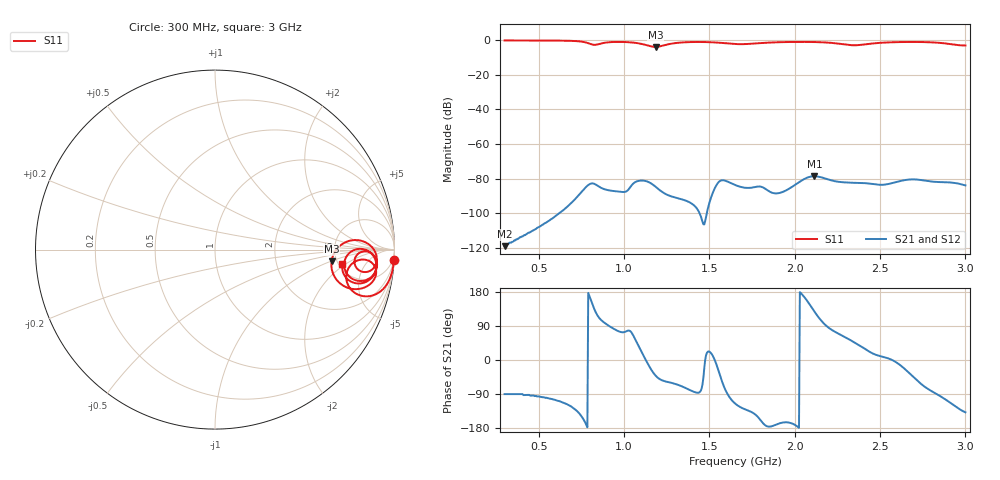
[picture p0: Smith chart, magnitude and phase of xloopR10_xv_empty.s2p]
! xloopR10_xv_empty, gap C 0.80 pF
! simulated by sim/fixtures_fdtd.py (S12 = S21, S22 not computed)
# HZ S RI R 50
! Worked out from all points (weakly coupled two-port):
!   541 points, 300 MHz to 3 GHz, reference 50 ohm
!   highest |S21| = -78.68 dB at 2.115 GHz (marker M1); lowest = -119.2 dB at 300 MHz (marker M2)
!   lowest |S11| = -3.7 dB at 1.185 GHz (marker M3), VSWR 4.76, Z = 226 - j51.2 ohm
!   |S11| at or under -10 dB: nowhere
!   |S22| runs from - to - dB; largest |S21 - S12| = 0
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3e8  0.9972 -0.0595  0 -1.1e-06  0 -1.1e-06  0 0
6.3e8  0.9732 -0.1644  -3.7e-06 -1.01e-05  -3.7e-06 -1.01e-05  0 0
7.5e8  0.8918 -0.2505  -3.44e-05 -2.13e-05  -3.44e-05 -2.13e-05  0 0
8.2e8  0.7314 -0.1622  -5.55e-05 4.54e-05  -5.55e-05 4.54e-05  0 0
8.65e8  0.8129 -0.0559  -1.46e-05 5.19e-05  -1.46e-05 5.19e-05  0 0
9.65e8  0.8974 -0.135  9.9e-06 4.08e-05  9.9e-06 4.08e-05  0 0
1.09e9  0.7867 -0.2205  7.33e-05 4.59e-05  7.33e-05 4.59e-05  0 0
1.185e9  0.6493 -0.0651  4.34e-05 -3.81e-05  4.34e-05 -3.81e-05  0 0
1.2e9  0.6614 -0.024  3.37e-05 -3.71e-05  3.37e-05 -3.71e-05  0 0
1.265e9  0.7833 0.0532  1.65e-05 -2.74e-05  1.65e-05 -2.74e-05  0 0
1.385e9  0.8961 -0.0224  3.8e-06 -2e-05  3.8e-06 -2e-05  0 0
1.545e9  0.8589 -0.1207  6.62e-05 -1.98e-05  6.62e-05 -1.98e-05  0 0
1.65e9  0.783 -0.0931  -2.71e-05 -5.93e-05  -2.71e-05 -5.93e-05  0 0
1.805e9  0.8419 -0.0095  -5.47e-05 -1.78e-05  -5.47e-05 -1.78e-05  0 0
2.1e9  0.8936 -0.1231  -8.58e-05 7.69e-05  -8.58e-05 7.69e-05  0 0
2.115e9  0.8895 -0.1304  -7.18e-05 9.17e-05  -7.18e-05 9.17e-05  0 0
2.25e9  0.7962 -0.1738  2.64e-05 7.69e-05  2.64e-05 7.69e-05  0 0
2.34e9  0.7196 -0.0869  4.95e-05 5.69e-05  4.95e-05 5.69e-05  0 0
2.425e9  0.7843 0.001  6.56e-05 3.12e-05  6.56e-05 3.12e-05  0 0
2.55e9  0.878 -0.029  6.96e-05 4.8e-06  6.96e-05 4.8e-06  0 0
2.87e9  0.8109 -0.1883  -1.4e-05 -7.73e-05  -1.4e-05 -7.73e-05  0 0
3e9  0.7097 -0.0829  -4.7e-05 -4.24e-05  -4.7e-05 -4.24e-05  0 0
